VERSION 5.7 ;
  NOWIREEXTENSIONATPIN ON ;
  DIVIDERCHAR "/" ;
  BUSBITCHARS "[]" ;
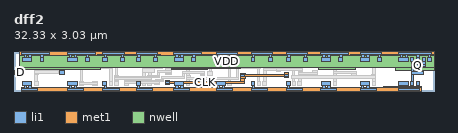
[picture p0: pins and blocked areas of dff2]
MACRO dff2
  CLASS BLOCK ;
  FOREIGN dff2 ;
  ORIGIN 1.100 0.400 ;
  SIZE 32.330 BY 3.030 ;
  PIN Q
    ANTENNADIFFAREA 0.660000 ;
    PORT
      LAYER li1 ;
        RECT 29.410 1.850 29.690 2.200 ;
        RECT 30.310 1.850 30.590 2.200 ;
        RECT 29.460 1.670 29.640 1.850 ;
        RECT 30.370 1.670 30.540 1.850 ;
        RECT 29.460 1.500 30.540 1.670 ;
        RECT 29.460 1.070 29.640 1.500 ;
        RECT 29.460 0.900 30.400 1.070 ;
        RECT 29.460 0.350 29.640 0.900 ;
        RECT 29.410 0.000 29.690 0.350 ;
    END
  END Q
  PIN CLK
    ANTENNAGATEAREA 0.792000 ;
    PORT
      LAYER li1 ;
        RECT 2.400 0.850 2.800 1.150 ;
        RECT 16.300 0.560 16.650 0.900 ;
        RECT 19.760 0.700 20.010 0.950 ;
        RECT 10.550 0.100 10.900 0.400 ;
      LAYER met1 ;
        RECT 16.310 0.900 16.710 0.910 ;
        RECT 19.760 0.900 20.050 0.990 ;
        RECT 16.310 0.710 20.050 0.900 ;
        RECT 16.310 0.570 16.710 0.710 ;
        RECT 19.760 0.680 20.050 0.710 ;
        RECT 19.760 0.670 20.010 0.680 ;
        RECT 10.550 0.340 10.900 0.400 ;
        RECT 16.320 0.340 16.650 0.570 ;
        RECT 10.550 0.180 16.650 0.340 ;
        RECT 10.550 0.100 10.900 0.180 ;
    END
  END CLK
  PIN VSS
    ANTENNADIFFAREA 4.622000 ;
    PORT
      LAYER li1 ;
        RECT -0.450 0.000 0.250 0.350 ;
        RECT 3.050 0.000 3.750 0.350 ;
        RECT 5.750 0.000 6.050 0.350 ;
        RECT 8.300 0.000 8.600 0.350 ;
        RECT 11.240 0.000 11.940 0.350 ;
        RECT 14.450 0.000 15.190 0.350 ;
        RECT 17.150 0.000 17.450 0.350 ;
        RECT 19.850 0.000 20.150 0.350 ;
        RECT 22.550 0.000 23.250 0.350 ;
        RECT 25.550 0.000 26.290 0.350 ;
        RECT 28.500 0.000 29.240 0.350 ;
        RECT 29.860 0.000 30.140 0.350 ;
        RECT -0.330 -0.170 -0.140 0.000 ;
        RECT 0.050 -0.170 0.240 0.000 ;
        RECT 3.170 -0.170 3.360 0.000 ;
        RECT 3.550 -0.170 3.740 0.000 ;
        RECT 5.850 -0.170 6.030 0.000 ;
        RECT 8.400 -0.170 8.580 0.000 ;
        RECT 11.360 -0.170 11.550 0.000 ;
        RECT 11.740 -0.170 11.930 0.000 ;
        RECT 14.550 -0.170 14.730 0.000 ;
        RECT 14.950 -0.170 15.130 0.000 ;
        RECT 17.250 -0.170 17.430 0.000 ;
        RECT 19.950 -0.170 20.130 0.000 ;
        RECT 22.670 -0.170 22.860 0.000 ;
        RECT 23.050 -0.170 23.240 0.000 ;
        RECT 25.650 -0.170 25.830 0.000 ;
        RECT 26.050 -0.170 26.230 0.000 ;
        RECT 28.620 -0.170 28.800 0.000 ;
        RECT 29.000 -0.170 29.180 0.000 ;
        RECT 29.920 -0.170 30.100 0.000 ;
        RECT -0.500 -0.350 0.740 -0.170 ;
        RECT 3.000 -0.350 4.240 -0.170 ;
        RECT 5.750 -0.350 6.990 -0.170 ;
        RECT 8.300 -0.350 9.540 -0.170 ;
        RECT 11.190 -0.350 12.430 -0.170 ;
        RECT 14.450 -0.350 15.690 -0.170 ;
        RECT 17.150 -0.350 18.390 -0.170 ;
        RECT 19.850 -0.350 21.090 -0.170 ;
        RECT 22.500 -0.350 23.740 -0.170 ;
        RECT 25.550 -0.350 26.790 -0.170 ;
        RECT 28.500 -0.350 30.150 -0.170 ;
      LAYER met1 ;
        RECT 27.340 -0.100 30.300 -0.090 ;
        RECT 4.300 -0.120 9.800 -0.100 ;
        RECT 13.990 -0.110 30.300 -0.100 ;
        RECT 13.370 -0.120 30.300 -0.110 ;
        RECT -0.550 -0.400 30.300 -0.120 ;
    END
  END VSS
  PIN D
    ANTENNAGATEAREA 0.480000 ;
    PORT
      LAYER li1 ;
        RECT -1.100 0.850 -0.700 1.150 ;
    END
  END D
  PIN VDD
    ANTENNADIFFAREA 8.058000 ;
    PORT
      LAYER nwell ;
        RECT 5.320 2.380 10.150 2.400 ;
        RECT 13.380 2.380 22.550 2.400 ;
        RECT 24.800 2.380 31.230 2.400 ;
        RECT -0.680 1.400 31.230 2.380 ;
        RECT -0.680 1.220 5.520 1.400 ;
        RECT 10.150 1.390 17.160 1.400 ;
        RECT 11.010 1.350 16.300 1.390 ;
        RECT 11.010 1.220 13.760 1.350 ;
        RECT 22.320 1.220 25.150 1.400 ;
        RECT 28.270 1.170 31.230 1.400 ;
      LAYER li1 ;
        RECT -0.500 2.380 1.650 2.570 ;
        RECT 3.000 2.380 5.150 2.570 ;
        RECT 5.750 2.380 7.400 2.580 ;
        RECT 8.300 2.380 9.950 2.580 ;
        RECT 11.190 2.380 13.340 2.570 ;
        RECT 14.450 2.380 16.100 2.580 ;
        RECT 17.150 2.380 18.800 2.580 ;
        RECT 19.850 2.380 21.500 2.580 ;
        RECT 22.500 2.380 24.650 2.570 ;
        RECT 25.550 2.380 27.200 2.580 ;
        RECT 28.500 2.380 31.050 2.570 ;
        RECT -0.330 2.200 -0.150 2.380 ;
        RECT 0.050 2.200 0.230 2.380 ;
        RECT 0.970 2.200 1.160 2.380 ;
        RECT 3.170 2.200 3.350 2.380 ;
        RECT 3.550 2.200 3.730 2.380 ;
        RECT 4.470 2.200 4.660 2.380 ;
        RECT 5.870 2.200 6.050 2.380 ;
        RECT 7.170 2.200 7.350 2.380 ;
        RECT 8.420 2.200 8.600 2.380 ;
        RECT 9.720 2.200 9.900 2.380 ;
        RECT 11.360 2.200 11.540 2.380 ;
        RECT 11.740 2.200 11.920 2.380 ;
        RECT 12.660 2.200 12.850 2.380 ;
        RECT 14.570 2.200 14.750 2.380 ;
        RECT 14.950 2.200 15.130 2.380 ;
        RECT 15.870 2.200 16.050 2.380 ;
        RECT 17.270 2.200 17.450 2.380 ;
        RECT 18.570 2.200 18.750 2.380 ;
        RECT 19.970 2.200 20.150 2.380 ;
        RECT 21.270 2.200 21.450 2.380 ;
        RECT 22.670 2.200 22.850 2.380 ;
        RECT 23.050 2.200 23.230 2.380 ;
        RECT 23.970 2.200 24.160 2.380 ;
        RECT 25.670 2.200 25.850 2.380 ;
        RECT 26.050 2.200 26.230 2.380 ;
        RECT 26.970 2.200 27.150 2.380 ;
        RECT 28.620 2.200 28.800 2.380 ;
        RECT 29.010 2.200 29.190 2.380 ;
        RECT 29.910 2.200 30.090 2.380 ;
        RECT 30.810 2.200 30.990 2.380 ;
        RECT -0.450 1.850 0.250 2.200 ;
        RECT 0.910 1.850 1.190 2.200 ;
        RECT 3.050 1.850 3.750 2.200 ;
        RECT 4.410 1.850 4.690 2.200 ;
        RECT 5.750 1.850 6.060 2.200 ;
        RECT 7.110 1.850 7.390 2.200 ;
        RECT 8.300 1.850 8.600 2.200 ;
        RECT 9.660 1.850 9.940 2.200 ;
        RECT 11.240 1.850 11.940 2.200 ;
        RECT 12.600 1.850 12.880 2.200 ;
        RECT 14.450 1.850 15.190 2.200 ;
        RECT 15.810 1.850 16.090 2.200 ;
        RECT 17.150 1.850 17.450 2.200 ;
        RECT 18.510 1.850 18.790 2.200 ;
        RECT 19.850 1.850 20.160 2.200 ;
        RECT 21.210 1.850 21.490 2.200 ;
        RECT 22.550 1.850 23.250 2.200 ;
        RECT 23.910 1.850 24.190 2.200 ;
        RECT 25.550 1.850 26.290 2.200 ;
        RECT 26.910 1.850 27.190 2.200 ;
        RECT 28.500 1.850 29.240 2.200 ;
        RECT 29.860 1.850 30.140 2.200 ;
        RECT 30.760 1.850 31.040 2.200 ;
      LAYER met1 ;
        RECT -0.680 2.620 5.320 2.630 ;
        RECT 5.700 2.620 31.230 2.630 ;
        RECT -0.680 2.350 31.230 2.620 ;
        RECT 5.320 2.340 5.700 2.350 ;
        RECT 7.600 2.340 8.200 2.350 ;
        RECT 24.900 2.340 25.440 2.350 ;
    END
  END VDD
  OBS
      LAYER li1 ;
        RECT 0.460 1.850 0.740 2.200 ;
        RECT 1.370 1.850 1.650 2.200 ;
        RECT 3.960 1.850 4.240 2.200 ;
        RECT 4.870 1.850 5.150 2.200 ;
        RECT 6.230 1.850 6.490 2.200 ;
        RECT 6.660 1.850 6.940 2.200 ;
        RECT 8.790 1.850 9.040 2.200 ;
        RECT 9.210 1.850 9.490 2.200 ;
        RECT 12.150 1.850 12.430 2.200 ;
        RECT 13.060 1.850 13.340 2.200 ;
        RECT 13.590 1.870 13.950 2.220 ;
        RECT 15.360 1.850 15.640 2.200 ;
        RECT 16.490 1.850 16.850 2.200 ;
        RECT 17.640 1.850 17.890 2.200 ;
        RECT 18.060 1.850 18.340 2.200 ;
        RECT 20.340 1.850 20.590 2.200 ;
        RECT 20.760 1.850 21.040 2.200 ;
        RECT 23.460 1.850 23.740 2.200 ;
        RECT 24.370 1.850 24.650 2.200 ;
        RECT 26.460 1.850 26.740 2.200 ;
        RECT 0.500 1.680 0.700 1.850 ;
        RECT 1.400 1.680 1.600 1.850 ;
        RECT 0.500 1.500 1.600 1.680 ;
        RECT 4.000 1.680 4.200 1.850 ;
        RECT 4.900 1.680 5.100 1.850 ;
        RECT 4.000 1.500 5.100 1.680 ;
        RECT 0.500 0.350 0.700 1.500 ;
        RECT 4.000 0.350 4.200 1.500 ;
        RECT 6.250 0.350 6.450 1.850 ;
        RECT 6.700 0.350 6.900 1.850 ;
        RECT 0.470 0.000 0.750 0.350 ;
        RECT 3.970 0.280 4.250 0.350 ;
        RECT 4.950 0.280 5.300 0.350 ;
        RECT 3.970 0.100 5.300 0.280 ;
        RECT 3.970 0.000 4.250 0.100 ;
        RECT 4.950 0.050 5.300 0.100 ;
        RECT 6.240 0.000 6.490 0.350 ;
        RECT 6.660 0.000 6.950 0.350 ;
        RECT 7.400 0.050 7.700 0.400 ;
        RECT 8.800 0.350 8.990 1.850 ;
        RECT 9.260 0.350 9.450 1.850 ;
        RECT 12.190 1.680 12.390 1.850 ;
        RECT 13.090 1.680 13.290 1.850 ;
        RECT 12.190 1.500 13.290 1.680 ;
        RECT 10.590 0.900 10.990 1.200 ;
        RECT 8.790 0.000 9.040 0.350 ;
        RECT 9.210 0.000 9.500 0.350 ;
        RECT 9.750 0.100 10.100 0.420 ;
        RECT 12.190 0.350 12.390 1.500 ;
        RECT 13.100 1.330 14.120 1.500 ;
        RECT 13.950 1.120 14.120 1.330 ;
        RECT 13.230 0.770 13.590 1.120 ;
        RECT 13.800 0.790 14.200 1.120 ;
        RECT 15.400 0.350 15.600 1.850 ;
        RECT 17.650 0.350 17.820 1.850 ;
        RECT 18.130 1.310 18.300 1.850 ;
        RECT 18.130 1.140 19.330 1.310 ;
        RECT 18.130 0.350 18.300 1.140 ;
        RECT 20.350 0.350 20.530 1.850 ;
        RECT 20.830 1.380 21.000 1.850 ;
        RECT 23.500 1.680 23.700 1.850 ;
        RECT 24.400 1.680 24.600 1.850 ;
        RECT 23.500 1.500 24.600 1.680 ;
        RECT 20.830 1.200 21.010 1.380 ;
        RECT 20.830 1.030 21.000 1.200 ;
        RECT 21.900 1.030 22.300 1.150 ;
        RECT 20.830 0.850 22.300 1.030 ;
        RECT 23.500 1.120 23.700 1.500 ;
        RECT 23.500 0.950 25.300 1.120 ;
        RECT 20.830 0.350 21.000 0.850 ;
        RECT 23.500 0.350 23.700 0.950 ;
        RECT 24.900 0.790 25.300 0.950 ;
        RECT 26.510 0.350 26.690 1.850 ;
        RECT 12.160 0.000 12.440 0.350 ;
        RECT 15.360 0.000 15.650 0.350 ;
        RECT 17.640 0.000 17.890 0.350 ;
        RECT 18.060 0.000 18.350 0.350 ;
        RECT 20.340 0.000 20.590 0.350 ;
        RECT 20.760 0.000 21.050 0.350 ;
        RECT 23.470 0.000 23.750 0.350 ;
        RECT 26.460 0.000 26.750 0.350 ;
      LAYER met1 ;
        RECT 13.600 2.200 14.080 2.210 ;
        RECT 13.590 2.190 16.500 2.200 ;
        RECT 13.590 2.050 16.850 2.190 ;
        RECT 13.590 2.000 14.080 2.050 ;
        RECT 13.600 1.910 14.080 2.000 ;
        RECT 16.490 1.980 16.850 2.050 ;
        RECT 13.600 1.880 13.940 1.910 ;
        RECT 16.500 1.890 16.850 1.980 ;
        RECT 16.500 1.860 16.840 1.890 ;
        RECT 10.150 1.740 13.430 1.750 ;
        RECT 14.080 1.740 14.900 1.750 ;
        RECT 10.150 1.600 14.900 1.740 ;
        RECT 15.320 1.600 15.650 1.620 ;
        RECT 6.230 1.540 6.490 1.600 ;
        RECT 2.110 1.350 6.490 1.540 ;
        RECT 10.150 1.440 10.300 1.600 ;
        RECT 14.750 1.450 15.650 1.600 ;
        RECT 17.620 1.550 17.880 1.580 ;
        RECT 2.100 1.340 6.490 1.350 ;
        RECT 0.460 1.160 0.760 1.200 ;
        RECT 2.100 1.160 2.290 1.340 ;
        RECT 6.230 1.300 6.490 1.340 ;
        RECT 9.610 1.300 10.300 1.440 ;
        RECT 15.320 1.330 15.650 1.450 ;
        RECT 16.000 1.350 17.880 1.550 ;
        RECT 20.780 1.370 21.090 1.440 ;
        RECT 19.110 1.350 21.090 1.370 ;
        RECT 0.460 0.940 2.290 1.160 ;
        RECT 8.770 1.000 9.750 1.300 ;
        RECT 10.590 1.150 10.990 1.300 ;
        RECT 8.800 0.990 9.750 1.000 ;
        RECT 9.950 1.000 10.990 1.150 ;
        RECT 13.240 1.100 13.580 1.110 ;
        RECT 0.460 0.900 0.760 0.940 ;
        RECT 9.950 0.800 10.100 1.000 ;
        RECT 10.590 0.910 10.990 1.000 ;
        RECT 11.850 0.950 13.580 1.100 ;
        RECT 6.640 0.700 6.960 0.760 ;
        RECT 9.210 0.700 10.100 0.800 ;
        RECT 11.850 0.750 11.990 0.950 ;
        RECT 13.230 0.900 13.580 0.950 ;
        RECT 6.640 0.650 10.100 0.700 ;
        RECT 6.640 0.510 9.470 0.650 ;
        RECT 10.250 0.600 11.990 0.750 ;
        RECT 12.160 0.650 12.470 0.800 ;
        RECT 13.240 0.780 13.580 0.900 ;
        RECT 16.010 0.670 16.150 1.350 ;
        RECT 17.620 1.320 17.880 1.350 ;
        RECT 19.100 1.190 21.090 1.350 ;
        RECT 19.100 1.100 19.400 1.190 ;
        RECT 20.780 1.120 21.090 1.190 ;
        RECT 19.110 1.070 19.400 1.100 ;
        RECT 12.160 0.630 12.600 0.650 ;
        RECT 13.750 0.630 16.150 0.670 ;
        RECT 6.640 0.440 6.960 0.510 ;
        RECT 10.250 0.500 10.400 0.600 ;
        RECT 12.160 0.510 16.150 0.630 ;
        RECT 20.280 0.770 20.590 0.830 ;
        RECT 26.420 0.770 26.760 0.850 ;
        RECT 20.280 0.600 26.760 0.770 ;
        RECT 20.280 0.530 20.590 0.600 ;
        RECT 26.420 0.550 26.760 0.600 ;
        RECT 9.820 0.420 10.400 0.500 ;
        RECT 12.450 0.490 16.150 0.510 ;
        RECT 9.750 0.370 10.400 0.420 ;
        RECT 7.700 0.350 10.400 0.370 ;
        RECT 7.700 0.330 10.100 0.350 ;
        RECT 7.410 0.190 10.100 0.330 ;
        RECT 7.410 0.050 7.710 0.190 ;
        RECT 9.750 0.100 10.100 0.190 ;
  END
END dff2
END LIBRARY

